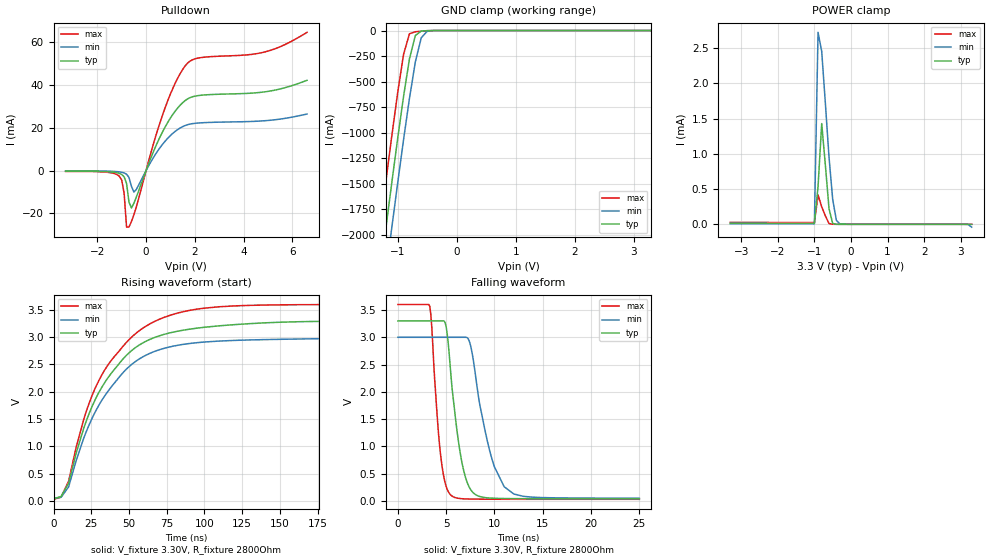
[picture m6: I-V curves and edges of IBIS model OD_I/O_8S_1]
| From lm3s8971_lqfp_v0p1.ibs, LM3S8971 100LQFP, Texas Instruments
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[Model]   OD_I/O_8S_1
Model_type   I/O_open_drain
Polarity   Inverting
Vinl = 1.26
Vinh = 2.04
Vmeas = 1.65
Rref = 2800
Vref = 3.3
| variable   typ   min   max
C_comp   9.739pF   9.739pF   9.739pF
[Model Spec]
Vinh+   1.91   1.78   2.04
Vinh-   1.90   1.76   2.03
Vinl+   1.40   1.27   1.54
Vinl-   1.39   1.26   1.53
| variable   typ   min   max
[Temperature Range]  25   85   -40
[Voltage Range]   3.3V   3.0V   3.6V
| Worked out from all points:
|   slope of the pulldown table from 0 to 0.495 V, typ, clamps not added: 35.8 ohm
|   GND clamp passes 1 mA (typ) near -0.48 V on its own axis
|   POWER clamp passes 1 mA (typ) near -0.73 V on its own axis
|   falling waveform, V_fixture 3.30V, R_fixture 2800Ohm: 20-80 % time 1.32ns typ, 2.02ns min, 884ps max; typ from 3.3 V to 0.038 V
|   rising waveform, V_fixture 3.30V, R_fixture 2800Ohm: 20-80 % time 34.2ns typ, 34ns min, 34.6ns max; typ from 0.038 V to 3.3 V
[Pulldown]
|  Voltage   I(typ)   I(min)   I(max)
-3.3V     -256.6uA   -145.6uA   -364.5uA
-1.1V     -1.273mA   -587.5uA   -2.567mA
-900mV    -2.885mA   -1.061mA   -10.54mA
-800mV    -5.993mA   -1.67mA    -26.39mA
-700mV    -14.71mA   -3.215mA   -26.33mA
-600mV    -17.43mA   -7.321mA   -23.73mA
-500mV    -15.26mA   -10mA      -20.66mA
700mV     18.62mA    12.61mA    26.75mA
1.2V      27.84mA    18.36mA    40.91mA
1.7V      33.44mA    21.41mA    50.13mA
4.9V      36.8mA     23.3mA     55.47mA
6.6V      42.15mA    26.42mA    64.53mA
[GND Clamp]
|  Voltage   I(typ)   I(min)   I(max)
-3.3V     -11.72A    -12.12A    -11.3A
-1.4V     -2.845A    -3.285A    -2.387A
-1.3V     -2.39A     -2.831A    -1.93A
-1.2V     -1.938A    -2.38A     -1.478A
-1.1V     -1.494A    -1.934A    -1.036A
-1V       -1.059A    -1.496A    -610.6mA
-900mV    -645mA     -1.069A    -232.9mA
-800mV    -277.1mA   -664.4mA   -31.59mA
-700mV    -48.56mA   -306.6mA   -12.09mA
-600mV    -5.558mA   -70.2mA    -6.272mA
-500mV    -1.167mA   -7.88mA    -2.167mA
3.3V      2.282nA    3.101uA    451.3pA
[POWER Clamp]
|  Voltage   I(typ)   I(min)   I(max)
-3.3V     15.18uA    8.315uA    27.48uA
-1V       14.14uA    7.74uA     25.63uA
-900mV    536uA      2.726mA    416.7uA
-800mV    1.43mA     2.454mA    247.6uA
-700mV    840.7uA    1.719mA    119.9uA
-600mV    221.2uA    951.5uA    11.58uA
-500mV    12.35uA    355.6uA    955.3nA
-400mV    305.2nA    58.59uA    44.3nA
-300mV    9.515nA    3.101uA    1.472nA
3.1V      1.302nA    -112.7nA   143.5pA
3.2V      1.207nA    -2.287uA   131.7pA
3.3V      -104.8pA   -40.34uA   119.2pA
[Ramp]
| variable   typ   min   max
dV/dt_f   1.96/1.32n   1.77/2.02n   2.14/0.88n
dV/dt_r   1.96/34.24n   1.77/34.00n   2.14/34.63n
R_load = 2800Ohm
[Falling Waveform]
V_fixture = 3.30V
V_fixture_min = 3.00V
V_fixture_max = 3.60V
R_fixture = 2800Ohm
|   Time   V(typ)   V(min)   V(max)
0s        3.3V       2.999V     3.6V
3.3ns     3.3V       2.999V     3.564V
4.4ns     3.3V       2.999V     871.9mV
5ns       3.186V     2.999V     262.6mV
5.5ns     2.279V     2.999V     103.5mV
6.4ns     933.9mV    2.999V     44.91mV
7.3ns     283.8mV    2.965V     35.56mV
9.4ns     54.75mV    993.6mV    31.55mV
11ns      44.17mV    260.9mV    30.7mV
25ns      37.97mV    50.43mV    29.46mV
[Rising Waveform]
V_fixture = 3.30V
V_fixture_min = 3.00V
V_fixture_max = 3.60V
R_fixture = 2800Ohm
|   Time   V(typ)   V(min)   V(max)
0s        38.08mV    50.7mV     29.48mV
5ns       80.81mV    66.81mV    69.32mV
10ns      324.3mV    257.9mV    361.9mV
20ns      1.329V     1.148V     1.491V
32ns      2.082V     1.844V     2.308V
49ns      2.687V     2.433V     2.925V
65ns      2.973V     2.718V     3.261V
85ns      3.124V     2.865V     3.461V
110ns     3.209V     2.93V      3.558V
250ns     3.298V     2.994V     3.599V
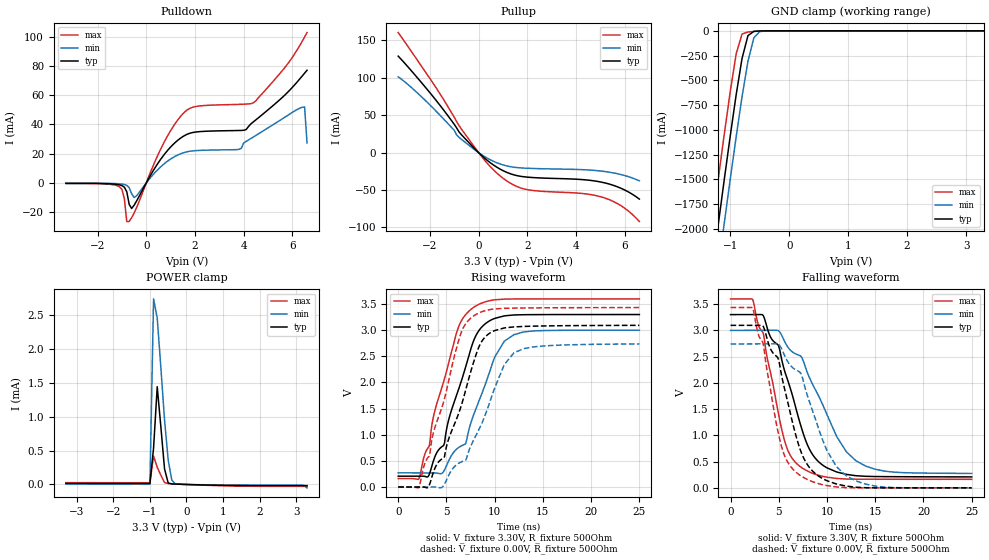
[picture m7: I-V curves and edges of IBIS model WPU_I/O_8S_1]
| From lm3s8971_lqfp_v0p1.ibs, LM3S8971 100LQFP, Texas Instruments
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[Model]   WPU_I/O_8S_1
Model_type   I/O
Vinl = 1.26
Vinh = 2.04
Vmeas = 1.65
| variable   typ   min   max
C_comp   9.739pF   9.739pF   9.739pF
[Model Spec]
Vinh+   1.91   1.78   2.04
Vinh-   1.90   1.76   2.03
Vinl+   1.40   1.27   1.54
Vinl-   1.39   1.26   1.53
| variable   typ   min   max
[Temperature Range]  25   85   -40
[Voltage Range]   3.3V   3.0V   3.6V
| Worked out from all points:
|   slope of the pulldown table from 0 to 0.495 V, typ, clamps not added: 35.8 ohm
|   slope of the pullup table from 0 to 0.495 V, typ, clamps not added: 35.8 ohm
|   GND clamp passes 1 mA (typ) near -0.48 V on its own axis
|   POWER clamp passes 1 mA (typ) near -0.73 V on its own axis
|   falling waveform, V_fixture 3.30V, R_fixture 500Ohm: 20-80 % time 2.93ns typ, 4.09ns min, 2.25ns max; typ from 3.3 V to 0.208 V
|   rising waveform, V_fixture 3.30V, R_fixture 500Ohm: 20-80 % time 2.83ns typ, 3.04ns min, 2.71ns max; typ from 0.208 V to 3.3 V
|   falling waveform, V_fixture 0.00V, R_fixture 500Ohm: 20-80 % time 2.55ns typ, 3.29ns min, 2.08ns max; typ from 3.09 V to 0 V
|   rising waveform, V_fixture 0.00V, R_fixture 500Ohm: 20-80 % time 3.13ns typ, 3.58ns min, 2.86ns max; typ from 0 V to 3.09 V
[Pulldown]
|  Voltage   I(typ)   I(min)   I(max)
-3.3V     -256.4uA   -145.5uA   -364.3uA
-1.1V     -1.272mA   -586.9uA   -2.565mA
-900mV    -2.884mA   -1.06mA    -10.53mA
-800mV    -5.991mA   -1.669mA   -26.38mA
-700mV    -14.71mA   -3.213mA   -26.31mA
-500mV    -15.24mA   -9.997mA   -20.64mA
600mV     16.38mA    11.14mA    23.43mA
1.5V      31.7mA     20.53mA    47.23mA
3.8V      35.88mA    22.99mA    53.74mA
4.4V      41.81mA    31.48mA    54.88mA
6.5V      75.06mA    51.95mA    99.78mA
6.6V      77.08mA    27.42mA    102.8mA
[Pullup]
|  Voltage   I(typ)   I(min)   I(max)
-3.3V     128.9mA    101.3mA    160.4mA
-2V       80.13mA    63.77mA    99.04mA
-1V       37.9mA     29.83mA    47.32mA
-700mV    23.8mA     17.69mA    31.27mA
300mV     -8.84mA    -6.3mA     -12.15mA
1V        -23.98mA   -16.37mA   -34.08mA
1.5V      -30.12mA   -19.69mA   -44.19mA
2V        -32.71mA   -20.86mA   -49.43mA
4.3V      -36.12mA   -22.8mA    -54.73mA
5.1V      -39.81mA   -24.88mA   -59.77mA
5.9V      -48.4mA    -29.75mA   -72.06mA
6.6V      -62.06mA   -37.61mA   -92.08mA
[GND Clamp]
|  Voltage   I(typ)   I(min)   I(max)
-3.3V     -11.72A    -12.12A    -11.3A
-1.4V     -2.845A    -3.285A    -2.387A
-1.3V     -2.39A     -2.831A    -1.93A
-1.2V     -1.938A    -2.38A     -1.478A
-1.1V     -1.494A    -1.934A    -1.036A
-1V       -1.059A    -1.496A    -610.6mA
-900mV    -645mA     -1.069A    -232.9mA
-800mV    -277.1mA   -664.4mA   -31.6mA
-700mV    -48.56mA   -306.6mA   -12.11mA
-600mV    -5.565mA   -70.2mA    -6.295mA
-500mV    -1.181mA   -7.883mA   -2.191mA
3.3V      2.282nA    6.919uA    -6.845uA
[POWER Clamp]
|  Voltage   I(typ)   I(min)   I(max)
-3.3V     15.18uA    8.315uA    27.48uA
-1V       14.14uA    7.74uA     25.63uA
-900mV    539.2uA    2.746mA    419.4uA
-800mV    1.446mA    2.463mA    255uA
-700mV    851uA      1.726mA    135.8uA
-600mV    231.3uA    957.3uA    27.23uA
-500mV    21.69uA    361.2uA    14.14uA
-400mV    7.764uA    63.51uA    10.49uA
-300mV    5.5uA      6.919uA    7.727uA
3.1V      -16.64uA   -9.947uA   -27.43uA
3.2V      -16.65uA   -12.11uA   -27.44uA
3.3V      -16.65uA   -49.87uA   -27.45uA
[Ramp]
| variable   typ   min   max
dV/dt_f   1.85/2.93n   1.63/4.09n   2.06/2.25n
dV/dt_r   1.85/3.13n   1.64/3.58n   2.06/2.86n
R_load = 500Ohm
[Falling Waveform]
V_fixture = 3.30V
V_fixture_min = 3.00V
V_fixture_max = 3.60V
R_fixture = 500Ohm
|   Time   V(typ)   V(min)   V(max)
0s        3.298V     2.996V     3.597V
2.3ns     3.298V     2.998V     3.585V
3.4ns     3.276V     2.998V     2.936V
5ns       2.692V     2.986V     1.378V
5.6ns     2.229V     2.79V      898.2mV
7.2ns     1.235V     2.517V     407.6mV
9.1ns     502mV      1.761V     241.2mV
11ns      302.2mV    979.7mV    178.7mV
13ns      230.9mV    515.7mV    165.4mV
25ns      208.4mV    274.1mV    162.4mV
[Rising Waveform]
V_fixture = 3.30V
V_fixture_min = 3.00V
V_fixture_max = 3.60V
R_fixture = 500Ohm
|   Time   V(typ)   V(min)   V(max)
0s        207.7mV    271.2mV    162.2mV
2.1ns     207.5mV    270.5mV    146.6mV
3.2ns     232.7mV    270.2mV    771.4mV
4.8ns     840.9mV    326mV      2.073V
6.1ns     1.784V     732.4mV    2.981V
7ns       2.303V     833.1mV    3.299V
7.7ns     2.739V     1.319V     3.42V
10ns      3.225V     2.483V     3.58V
12ns      3.291V     2.913V     3.596V
25ns      3.299V     2.999V     3.598V
[Falling Waveform]
V_fixture = 0.00V
V_fixture_min = 0.00V
V_fixture_max = 0.00V
R_fixture = 500Ohm
|   Time   V(typ)   V(min)   V(max)
0s        3.093V     2.739V     3.433V
2.3ns     3.093V     2.74V      3.421V
3.4ns     3.071V     2.74V      2.73V
4.9ns     2.477V     2.739V     1.086V
5.3ns     2.13V      2.643V     778.5mV
7ns       852.7mV    2.223V     266.5mV
8.1ns     406.5mV    1.685V     148mV
10ns      135.4mV    708.2mV    42.63mV
12ns      33.32mV    230.4mV    3.826mV
25ns      39.49uV    90.22uV    23.61uV
[Rising Waveform]
V_fixture = 0.00V
V_fixture_min = 0.00V
V_fixture_max = 0.00V
R_fixture = 500Ohm
|   Time   V(typ)   V(min)   V(max)
0s        400.4uV    2.354mV    176.5uV
2.1ns     186.8uV    994.6uV    -14.86mV
3.1ns     -4.819mV   566.4uV    569mV
4.6ns     543.7mV    4.102mV    1.563V
6.4ns     1.478V     468.1mV    2.886V
7.7ns     2.319V     853.1mV    3.256V
9.1ns     2.885V     1.418V     3.377V
11ns      3.043V     2.342V     3.417V
12ns      3.062V     2.567V     3.421V
25ns      3.092V     2.736V     3.432V
